VERSION 5.4 ;
NAMESCASESENSITIVE ON ;
BUSBITCHARS "[]" ;
DIVIDERCHAR "/" ;
UNITS
  DATABASE MICRONS 2000 ;
END UNITS
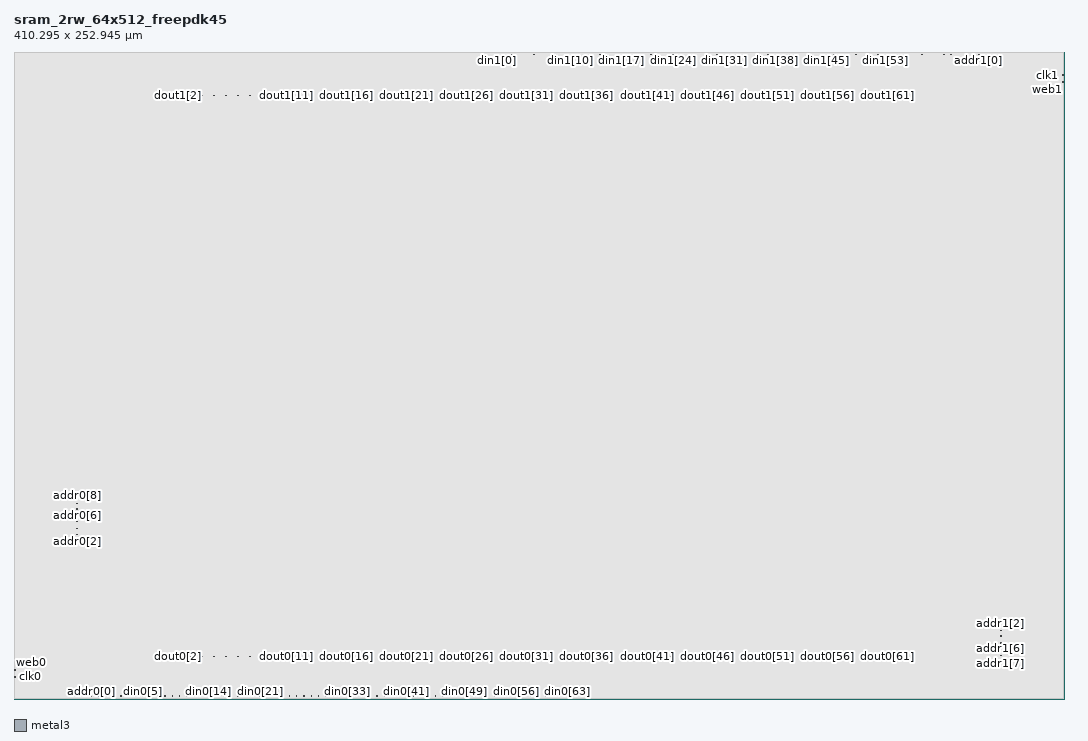
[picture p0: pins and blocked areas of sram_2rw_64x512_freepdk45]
MACRO sram_2rw_64x512_freepdk45
   CLASS BLOCK ;
   SIZE 410.295 BY 252.945 ;
   SYMMETRY X Y R90 ;
   PIN din0[0]
      DIRECTION INPUT ;
      PORT
         LAYER metal3 ;
         RECT  36.015 1.0375 36.15 1.1725 ;
      END
   END din0[0]
   PIN din0[1]
      DIRECTION INPUT ;
      PORT
         LAYER metal3 ;
         RECT  38.875 1.0375 39.01 1.1725 ;
      END
   END din0[1]
   PIN din0[2]
      DIRECTION INPUT ;
      PORT
         LAYER metal3 ;
         RECT  41.735 1.0375 41.87 1.1725 ;
      END
   END din0[2]
   PIN din0[3]
      DIRECTION INPUT ;
      PORT
         LAYER metal3 ;
         RECT  44.595 1.0375 44.73 1.1725 ;
      END
   END din0[3]
   PIN din0[4]
      DIRECTION INPUT ;
      PORT
         LAYER metal3 ;
         RECT  47.455 1.0375 47.59 1.1725 ;
      END
   END din0[4]
   PIN din0[5]
      DIRECTION INPUT ;
      PORT
         LAYER metal3 ;
         RECT  50.315 1.0375 50.45 1.1725 ;
      END
   END din0[5]
   PIN din0[6]
      DIRECTION INPUT ;
      PORT
         LAYER metal3 ;
         RECT  53.175 1.0375 53.31 1.1725 ;
      END
   END din0[6]
   PIN din0[7]
      DIRECTION INPUT ;
      PORT
         LAYER metal3 ;
         RECT  56.035 1.0375 56.17 1.1725 ;
      END
   END din0[7]
   PIN din0[8]
      DIRECTION INPUT ;
      PORT
         LAYER metal3 ;
         RECT  58.895 1.0375 59.03 1.1725 ;
      END
   END din0[8]
   PIN din0[9]
      DIRECTION INPUT ;
      PORT
         LAYER metal3 ;
         RECT  61.755 1.0375 61.89 1.1725 ;
      END
   END din0[9]
   PIN din0[10]
      DIRECTION INPUT ;
      PORT
         LAYER metal3 ;
         RECT  64.615 1.0375 64.75 1.1725 ;
      END
   END din0[10]
   PIN din0[11]
      DIRECTION INPUT ;
      PORT
         LAYER metal3 ;
         RECT  67.475 1.0375 67.61 1.1725 ;
      END
   END din0[11]
   PIN din0[12]
      DIRECTION INPUT ;
      PORT
         LAYER metal3 ;
         RECT  70.335 1.0375 70.47 1.1725 ;
      END
   END din0[12]
   PIN din0[13]
      DIRECTION INPUT ;
      PORT
         LAYER metal3 ;
         RECT  73.195 1.0375 73.33 1.1725 ;
      END
   END din0[13]
   PIN din0[14]
      DIRECTION INPUT ;
      PORT
         LAYER metal3 ;
         RECT  76.055 1.0375 76.19 1.1725 ;
      END
   END din0[14]
   PIN din0[15]
      DIRECTION INPUT ;
      PORT
         LAYER metal3 ;
         RECT  78.915 1.0375 79.05 1.1725 ;
      END
   END din0[15]
   PIN din0[16]
      DIRECTION INPUT ;
      PORT
         LAYER metal3 ;
         RECT  81.775 1.0375 81.91 1.1725 ;
      END
   END din0[16]
   PIN din0[17]
      DIRECTION INPUT ;
      PORT
         LAYER metal3 ;
         RECT  84.635 1.0375 84.77 1.1725 ;
      END
   END din0[17]
   PIN din0[18]
      DIRECTION INPUT ;
      PORT
         LAYER metal3 ;
         RECT  87.495 1.0375 87.63 1.1725 ;
      END
   END din0[18]
   PIN din0[19]
      DIRECTION INPUT ;
      PORT
         LAYER metal3 ;
         RECT  90.355 1.0375 90.49 1.1725 ;
      END
   END din0[19]
   PIN din0[20]
      DIRECTION INPUT ;
      PORT
         LAYER metal3 ;
         RECT  93.215 1.0375 93.35 1.1725 ;
      END
   END din0[20]
   PIN din0[21]
      DIRECTION INPUT ;
      PORT
         LAYER metal3 ;
         RECT  96.075 1.0375 96.21 1.1725 ;
      END
   END din0[21]
   PIN din0[22]
      DIRECTION INPUT ;
      PORT
         LAYER metal3 ;
         RECT  98.935 1.0375 99.07 1.1725 ;
      END
   END din0[22]
   PIN din0[23]
      DIRECTION INPUT ;
      PORT
         LAYER metal3 ;
         RECT  101.795 1.0375 101.93 1.1725 ;
      END
   END din0[23]
   PIN din0[24]
      DIRECTION INPUT ;
      PORT
         LAYER metal3 ;
         RECT  104.655 1.0375 104.79 1.1725 ;
      END
   END din0[24]
   PIN din0[25]
      DIRECTION INPUT ;
      PORT
         LAYER metal3 ;
         RECT  107.515 1.0375 107.65 1.1725 ;
      END
   END din0[25]
   PIN din0[26]
      DIRECTION INPUT ;
      PORT
         LAYER metal3 ;
         RECT  110.375 1.0375 110.51 1.1725 ;
      END
   END din0[26]
   PIN din0[27]
      DIRECTION INPUT ;
      PORT
         LAYER metal3 ;
         RECT  113.235 1.0375 113.37 1.1725 ;
      END
   END din0[27]
   PIN din0[28]
      DIRECTION INPUT ;
      PORT
         LAYER metal3 ;
         RECT  116.095 1.0375 116.23 1.1725 ;
      END
   END din0[28]
   PIN din0[29]
      DIRECTION INPUT ;
      PORT
         LAYER metal3 ;
         RECT  118.955 1.0375 119.09 1.1725 ;
      END
   END din0[29]
   PIN din0[30]
      DIRECTION INPUT ;
      PORT
         LAYER metal3 ;
         RECT  121.815 1.0375 121.95 1.1725 ;
      END
   END din0[30]
   PIN din0[31]
      DIRECTION INPUT ;
      PORT
         LAYER metal3 ;
         RECT  124.675 1.0375 124.81 1.1725 ;
      END
   END din0[31]
   PIN din0[32]
      DIRECTION INPUT ;
      PORT
         LAYER metal3 ;
         RECT  127.535 1.0375 127.67 1.1725 ;
      END
   END din0[32]
   PIN din0[33]
      DIRECTION INPUT ;
      PORT
         LAYER metal3 ;
         RECT  130.395 1.0375 130.53 1.1725 ;
      END
   END din0[33]
   PIN din0[34]
      DIRECTION INPUT ;
      PORT
         LAYER metal3 ;
         RECT  133.255 1.0375 133.39 1.1725 ;
      END
   END din0[34]
   PIN din0[35]
      DIRECTION INPUT ;
      PORT
         LAYER metal3 ;
         RECT  136.115 1.0375 136.25 1.1725 ;
      END
   END din0[35]
   PIN din0[36]
      DIRECTION INPUT ;
      PORT
         LAYER metal3 ;
         RECT  138.975 1.0375 139.11 1.1725 ;
      END
   END din0[36]
   PIN din0[37]
      DIRECTION INPUT ;
      PORT
         LAYER metal3 ;
         RECT  141.835 1.0375 141.97 1.1725 ;
      END
   END din0[37]
   PIN din0[38]
      DIRECTION INPUT ;
      PORT
         LAYER metal3 ;
         RECT  144.695 1.0375 144.83 1.1725 ;
      END
   END din0[38]
   PIN din0[39]
      DIRECTION INPUT ;
      PORT
         LAYER metal3 ;
         RECT  147.555 1.0375 147.69 1.1725 ;
      END
   END din0[39]
   PIN din0[40]
      DIRECTION INPUT ;
      PORT
         LAYER metal3 ;
         RECT  150.415 1.0375 150.55 1.1725 ;
      END
   END din0[40]
   PIN din0[41]
      DIRECTION INPUT ;
      PORT
         LAYER metal3 ;
         RECT  153.275 1.0375 153.41 1.1725 ;
      END
   END din0[41]
   PIN din0[42]
      DIRECTION INPUT ;
      PORT
         LAYER metal3 ;
         RECT  156.135 1.0375 156.27 1.1725 ;
      END
   END din0[42]
   PIN din0[43]
      DIRECTION INPUT ;
      PORT
         LAYER metal3 ;
         RECT  158.995 1.0375 159.13 1.1725 ;
      END
   END din0[43]
   PIN din0[44]
      DIRECTION INPUT ;
      PORT
         LAYER metal3 ;
         RECT  161.855 1.0375 161.99 1.1725 ;
      END
   END din0[44]
   PIN din0[45]
      DIRECTION INPUT ;
      PORT
         LAYER metal3 ;
         RECT  164.715 1.0375 164.85 1.1725 ;
      END
   END din0[45]
   PIN din0[46]
      DIRECTION INPUT ;
      PORT
         LAYER metal3 ;
         RECT  167.575 1.0375 167.71 1.1725 ;
      END
   END din0[46]
   PIN din0[47]
      DIRECTION INPUT ;
      PORT
         LAYER metal3 ;
         RECT  170.435 1.0375 170.57 1.1725 ;
      END
   END din0[47]
   PIN din0[48]
      DIRECTION INPUT ;
      PORT
         LAYER metal3 ;
         RECT  173.295 1.0375 173.43 1.1725 ;
      END
   END din0[48]
   PIN din0[49]
      DIRECTION INPUT ;
      PORT
         LAYER metal3 ;
         RECT  176.155 1.0375 176.29 1.1725 ;
      END
   END din0[49]
   PIN din0[50]
      DIRECTION INPUT ;
      PORT
         LAYER metal3 ;
         RECT  179.015 1.0375 179.15 1.1725 ;
      END
   END din0[50]
   PIN din0[51]
      DIRECTION INPUT ;
      PORT
         LAYER metal3 ;
         RECT  181.875 1.0375 182.01 1.1725 ;
      END
   END din0[51]
   PIN din0[52]
      DIRECTION INPUT ;
      PORT
         LAYER metal3 ;
         RECT  184.735 1.0375 184.87 1.1725 ;
      END
   END din0[52]
   PIN din0[53]
      DIRECTION INPUT ;
      PORT
         LAYER metal3 ;
         RECT  187.595 1.0375 187.73 1.1725 ;
      END
   END din0[53]
   PIN din0[54]
      DIRECTION INPUT ;
      PORT
         LAYER metal3 ;
         RECT  190.455 1.0375 190.59 1.1725 ;
      END
   END din0[54]
   PIN din0[55]
      DIRECTION INPUT ;
      PORT
         LAYER metal3 ;
         RECT  193.315 1.0375 193.45 1.1725 ;
      END
   END din0[55]
   PIN din0[56]
      DIRECTION INPUT ;
      PORT
         LAYER metal3 ;
         RECT  196.175 1.0375 196.31 1.1725 ;
      END
   END din0[56]
   PIN din0[57]
      DIRECTION INPUT ;
      PORT
         LAYER metal3 ;
         RECT  199.035 1.0375 199.17 1.1725 ;
      END
   END din0[57]
   PIN din0[58]
      DIRECTION INPUT ;
      PORT
         LAYER metal3 ;
         RECT  201.895 1.0375 202.03 1.1725 ;
      END
   END din0[58]
   PIN din0[59]
      DIRECTION INPUT ;
      PORT
         LAYER metal3 ;
         RECT  204.755 1.0375 204.89 1.1725 ;
      END
   END din0[59]
   PIN din0[60]
      DIRECTION INPUT ;
      PORT
         LAYER metal3 ;
         RECT  207.615 1.0375 207.75 1.1725 ;
      END
   END din0[60]
   PIN din0[61]
      DIRECTION INPUT ;
      PORT
         LAYER metal3 ;
         RECT  210.475 1.0375 210.61 1.1725 ;
      END
   END din0[61]
   PIN din0[62]
      DIRECTION INPUT ;
      PORT
         LAYER metal3 ;
         RECT  213.335 1.0375 213.47 1.1725 ;
      END
   END din0[62]
   PIN din0[63]
      DIRECTION INPUT ;
      PORT
         LAYER metal3 ;
         RECT  216.195 1.0375 216.33 1.1725 ;
      END
   END din0[63]
   PIN din1[0]
      DIRECTION INPUT ;
      PORT
         LAYER metal3 ;
         RECT  188.81 251.7725 188.945 251.9075 ;
      END
   END din1[0]
   PIN din1[1]
      DIRECTION INPUT ;
      PORT
         LAYER metal3 ;
         RECT  191.67 251.7725 191.805 251.9075 ;
      END
   END din1[1]
   PIN din1[2]
      DIRECTION INPUT ;
      PORT
         LAYER metal3 ;
         RECT  194.53 251.7725 194.665 251.9075 ;
      END
   END din1[2]
   PIN din1[3]
      DIRECTION INPUT ;
      PORT
         LAYER metal3 ;
         RECT  197.39 251.7725 197.525 251.9075 ;
      END
   END din1[3]
   PIN din1[4]
      DIRECTION INPUT ;
      PORT
         LAYER metal3 ;
         RECT  200.25 251.7725 200.385 251.9075 ;
      END
   END din1[4]
   PIN din1[5]
      DIRECTION INPUT ;
      PORT
         LAYER metal3 ;
         RECT  203.11 251.7725 203.245 251.9075 ;
      END
   END din1[5]
   PIN din1[6]
      DIRECTION INPUT ;
      PORT
         LAYER metal3 ;
         RECT  205.97 251.7725 206.105 251.9075 ;
      END
   END din1[6]
   PIN din1[7]
      DIRECTION INPUT ;
      PORT
         LAYER metal3 ;
         RECT  208.83 251.7725 208.965 251.9075 ;
      END
   END din1[7]
   PIN din1[8]
      DIRECTION INPUT ;
      PORT
         LAYER metal3 ;
         RECT  211.69 251.7725 211.825 251.9075 ;
      END
   END din1[8]
   PIN din1[9]
      DIRECTION INPUT ;
      PORT
         LAYER metal3 ;
         RECT  214.55 251.7725 214.685 251.9075 ;
      END
   END din1[9]
   PIN din1[10]
      DIRECTION INPUT ;
      PORT
         LAYER metal3 ;
         RECT  217.41 251.7725 217.545 251.9075 ;
      END
   END din1[10]
   PIN din1[11]
      DIRECTION INPUT ;
      PORT
         LAYER metal3 ;
         RECT  220.27 251.7725 220.405 251.9075 ;
      END
   END din1[11]
   PIN din1[12]
      DIRECTION INPUT ;
      PORT
         LAYER metal3 ;
         RECT  223.13 251.7725 223.265 251.9075 ;
      END
   END din1[12]
   PIN din1[13]
      DIRECTION INPUT ;
      PORT
         LAYER metal3 ;
         RECT  225.99 251.7725 226.125 251.9075 ;
      END
   END din1[13]
   PIN din1[14]
      DIRECTION INPUT ;
      PORT
         LAYER metal3 ;
         RECT  228.85 251.7725 228.985 251.9075 ;
      END
   END din1[14]
   PIN din1[15]
      DIRECTION INPUT ;
      PORT
         LAYER metal3 ;
         RECT  231.71 251.7725 231.845 251.9075 ;
      END
   END din1[15]
   PIN din1[16]
      DIRECTION INPUT ;
      PORT
         LAYER metal3 ;
         RECT  234.57 251.7725 234.705 251.9075 ;
      END
   END din1[16]
   PIN din1[17]
      DIRECTION INPUT ;
      PORT
         LAYER metal3 ;
         RECT  237.43 251.7725 237.565 251.9075 ;
      END
   END din1[17]
   PIN din1[18]
      DIRECTION INPUT ;
      PORT
         LAYER metal3 ;
         RECT  240.29 251.7725 240.425 251.9075 ;
      END
   END din1[18]
   PIN din1[19]
      DIRECTION INPUT ;
      PORT
         LAYER metal3 ;
         RECT  243.15 251.7725 243.285 251.9075 ;
      END
   END din1[19]
   PIN din1[20]
      DIRECTION INPUT ;
      PORT
         LAYER metal3 ;
         RECT  246.01 251.7725 246.145 251.9075 ;
      END
   END din1[20]
   PIN din1[21]
      DIRECTION INPUT ;
      PORT
         LAYER metal3 ;
         RECT  248.87 251.7725 249.005 251.9075 ;
      END
   END din1[21]
   PIN din1[22]
      DIRECTION INPUT ;
      PORT
         LAYER metal3 ;
         RECT  251.73 251.7725 251.865 251.9075 ;
      END
   END din1[22]
   PIN din1[23]
      DIRECTION INPUT ;
      PORT
         LAYER metal3 ;
         RECT  254.59 251.7725 254.725 251.9075 ;
      END
   END din1[23]
   PIN din1[24]
      DIRECTION INPUT ;
      PORT
         LAYER metal3 ;
         RECT  257.45 251.7725 257.585 251.9075 ;
      END
   END din1[24]
   PIN din1[25]
      DIRECTION INPUT ;
      PORT
         LAYER metal3 ;
         RECT  260.31 251.7725 260.445 251.9075 ;
      END
   END din1[25]
   PIN din1[26]
      DIRECTION INPUT ;
      PORT
         LAYER metal3 ;
         RECT  263.17 251.7725 263.305 251.9075 ;
      END
   END din1[26]
   PIN din1[27]
      DIRECTION INPUT ;
      PORT
         LAYER metal3 ;
         RECT  266.03 251.7725 266.165 251.9075 ;
      END
   END din1[27]
   PIN din1[28]
      DIRECTION INPUT ;
      PORT
         LAYER metal3 ;
         RECT  268.89 251.7725 269.025 251.9075 ;
      END
   END din1[28]
   PIN din1[29]
      DIRECTION INPUT ;
      PORT
         LAYER metal3 ;
         RECT  271.75 251.7725 271.885 251.9075 ;
      END
   END din1[29]
   PIN din1[30]
      DIRECTION INPUT ;
      PORT
         LAYER metal3 ;
         RECT  274.61 251.7725 274.745 251.9075 ;
      END
   END din1[30]
   PIN din1[31]
      DIRECTION INPUT ;
      PORT
         LAYER metal3 ;
         RECT  277.47 251.7725 277.605 251.9075 ;
      END
   END din1[31]
   PIN din1[32]
      DIRECTION INPUT ;
      PORT
         LAYER metal3 ;
         RECT  280.33 251.7725 280.465 251.9075 ;
      END
   END din1[32]
   PIN din1[33]
      DIRECTION INPUT ;
      PORT
         LAYER metal3 ;
         RECT  283.19 251.7725 283.325 251.9075 ;
      END
   END din1[33]
   PIN din1[34]
      DIRECTION INPUT ;
      PORT
         LAYER metal3 ;
         RECT  286.05 251.7725 286.185 251.9075 ;
      END
   END din1[34]
   PIN din1[35]
      DIRECTION INPUT ;
      PORT
         LAYER metal3 ;
         RECT  288.91 251.7725 289.045 251.9075 ;
      END
   END din1[35]
   PIN din1[36]
      DIRECTION INPUT ;
      PORT
         LAYER metal3 ;
         RECT  291.77 251.7725 291.905 251.9075 ;
      END
   END din1[36]
   PIN din1[37]
      DIRECTION INPUT ;
      PORT
         LAYER metal3 ;
         RECT  294.63 251.7725 294.765 251.9075 ;
      END
   END din1[37]
   PIN din1[38]
      DIRECTION INPUT ;
      PORT
         LAYER metal3 ;
         RECT  297.49 251.7725 297.625 251.9075 ;
      END
   END din1[38]
   PIN din1[39]
      DIRECTION INPUT ;
      PORT
         LAYER metal3 ;
         RECT  300.35 251.7725 300.485 251.9075 ;
      END
   END din1[39]
   PIN din1[40]
      DIRECTION INPUT ;
      PORT
         LAYER metal3 ;
         RECT  303.21 251.7725 303.345 251.9075 ;
      END
   END din1[40]
   PIN din1[41]
      DIRECTION INPUT ;
      PORT
         LAYER metal3 ;
         RECT  306.07 251.7725 306.205 251.9075 ;
      END
   END din1[41]
   PIN din1[42]
      DIRECTION INPUT ;
      PORT
         LAYER metal3 ;
         RECT  308.93 251.7725 309.065 251.9075 ;
      END
   END din1[42]
   PIN din1[43]
      DIRECTION INPUT ;
      PORT
         LAYER metal3 ;
         RECT  311.79 251.7725 311.925 251.9075 ;
      END
   END din1[43]
   PIN din1[44]
      DIRECTION INPUT ;
      PORT
         LAYER metal3 ;
         RECT  314.65 251.7725 314.785 251.9075 ;
      END
   END din1[44]
   PIN din1[45]
      DIRECTION INPUT ;
      PORT
         LAYER metal3 ;
         RECT  317.51 251.7725 317.645 251.9075 ;
      END
   END din1[45]
   PIN din1[46]
      DIRECTION INPUT ;
      PORT
         LAYER metal3 ;
         RECT  320.37 251.7725 320.505 251.9075 ;
      END
   END din1[46]
   PIN din1[47]
      DIRECTION INPUT ;
      PORT
         LAYER metal3 ;
         RECT  323.23 251.7725 323.365 251.9075 ;
      END
   END din1[47]
   PIN din1[48]
      DIRECTION INPUT ;
      PORT
         LAYER metal3 ;
         RECT  326.09 251.7725 326.225 251.9075 ;
      END
   END din1[48]
   PIN din1[49]
      DIRECTION INPUT ;
      PORT
         LAYER metal3 ;
         RECT  328.95 251.7725 329.085 251.9075 ;
      END
   END din1[49]
   PIN din1[50]
      DIRECTION INPUT ;
      PORT
         LAYER metal3 ;
         RECT  331.81 251.7725 331.945 251.9075 ;
      END
   END din1[50]
   PIN din1[51]
      DIRECTION INPUT ;
      PORT
         LAYER metal3 ;
         RECT  334.67 251.7725 334.805 251.9075 ;
      END
   END din1[51]
   PIN din1[52]
      DIRECTION INPUT ;
      PORT
         LAYER metal3 ;
         RECT  337.53 251.7725 337.665 251.9075 ;
      END
   END din1[52]
   PIN din1[53]
      DIRECTION INPUT ;
      PORT
         LAYER metal3 ;
         RECT  340.39 251.7725 340.525 251.9075 ;
      END
   END din1[53]
   PIN din1[54]
      DIRECTION INPUT ;
      PORT
         LAYER metal3 ;
         RECT  343.25 251.7725 343.385 251.9075 ;
      END
   END din1[54]
   PIN din1[55]
      DIRECTION INPUT ;
      PORT
         LAYER metal3 ;
         RECT  346.11 251.7725 346.245 251.9075 ;
      END
   END din1[55]
   PIN din1[56]
      DIRECTION INPUT ;
      PORT
         LAYER metal3 ;
         RECT  348.97 251.7725 349.105 251.9075 ;
      END
   END din1[56]
   PIN din1[57]
      DIRECTION INPUT ;
      PORT
         LAYER metal3 ;
         RECT  351.83 251.7725 351.965 251.9075 ;
      END
   END din1[57]
   PIN din1[58]
      DIRECTION INPUT ;
      PORT
         LAYER metal3 ;
         RECT  354.69 251.7725 354.825 251.9075 ;
      END
   END din1[58]
   PIN din1[59]
      DIRECTION INPUT ;
      PORT
         LAYER metal3 ;
         RECT  357.55 251.7725 357.685 251.9075 ;
      END
   END din1[59]
   PIN din1[60]
      DIRECTION INPUT ;
      PORT
         LAYER metal3 ;
         RECT  360.41 251.7725 360.545 251.9075 ;
      END
   END din1[60]
   PIN din1[61]
      DIRECTION INPUT ;
      PORT
         LAYER metal3 ;
         RECT  363.27 251.7725 363.405 251.9075 ;
      END
   END din1[61]
   PIN din1[62]
      DIRECTION INPUT ;
      PORT
         LAYER metal3 ;
         RECT  366.13 251.7725 366.265 251.9075 ;
      END
   END din1[62]
   PIN din1[63]
      DIRECTION INPUT ;
      PORT
         LAYER metal3 ;
         RECT  368.99 251.7725 369.125 251.9075 ;
      END
   END din1[63]
   PIN addr0[0]
      DIRECTION INPUT ;
      PORT
         LAYER metal3 ;
         RECT  30.295 1.0375 30.43 1.1725 ;
      END
   END addr0[0]
   PIN addr0[1]
      DIRECTION INPUT ;
      PORT
         LAYER metal3 ;
         RECT  33.155 1.0375 33.29 1.1725 ;
      END
   END addr0[1]
   PIN addr0[2]
      DIRECTION INPUT ;
      PORT
         LAYER metal3 ;
         RECT  24.575 61.5825 24.71 61.7175 ;
      END
   END addr0[2]
   PIN addr0[3]
      DIRECTION INPUT ;
      PORT
         LAYER metal3 ;
         RECT  24.575 64.3125 24.71 64.4475 ;
      END
   END addr0[3]
   PIN addr0[4]
      DIRECTION INPUT ;
      PORT
         LAYER metal3 ;
         RECT  24.575 66.5225 24.71 66.6575 ;
      END
   END addr0[4]
   PIN addr0[5]
      DIRECTION INPUT ;
      PORT
         LAYER metal3 ;
         RECT  24.575 69.2525 24.71 69.3875 ;
      END
   END addr0[5]
   PIN addr0[6]
      DIRECTION INPUT ;
      PORT
         LAYER metal3 ;
         RECT  24.575 71.4625 24.71 71.5975 ;
      END
   END addr0[6]
   PIN addr0[7]
      DIRECTION INPUT ;
      PORT
         LAYER metal3 ;
         RECT  24.575 74.1925 24.71 74.3275 ;
      END
   END addr0[7]
   PIN addr0[8]
      DIRECTION INPUT ;
      PORT
         LAYER metal3 ;
         RECT  24.575 76.4025 24.71 76.5375 ;
      END
   END addr0[8]
   PIN addr1[0]
      DIRECTION INPUT ;
      PORT
         LAYER metal3 ;
         RECT  377.005 251.7725 377.14 251.9075 ;
      END
   END addr1[0]
   PIN addr1[1]
      DIRECTION INPUT ;
      PORT
         LAYER metal3 ;
         RECT  374.145 251.7725 374.28 251.9075 ;
      END
   END addr1[1]
   PIN addr1[2]
      DIRECTION INPUT ;
      PORT
         LAYER metal3 ;
         RECT  385.585 29.4725 385.72 29.6075 ;
      END
   END addr1[2]
   PIN addr1[3]
      DIRECTION INPUT ;
      PORT
         LAYER metal3 ;
         RECT  385.585 26.7425 385.72 26.8775 ;
      END
   END addr1[3]
   PIN addr1[4]
      DIRECTION INPUT ;
      PORT
         LAYER metal3 ;
         RECT  385.585 24.5325 385.72 24.6675 ;
      END
   END addr1[4]
   PIN addr1[5]
      DIRECTION INPUT ;
      PORT
         LAYER metal3 ;
         RECT  385.585 21.8025 385.72 21.9375 ;
      END
   END addr1[5]
   PIN addr1[6]
      DIRECTION INPUT ;
      PORT
         LAYER metal3 ;
         RECT  385.585 19.5925 385.72 19.7275 ;
      END
   END addr1[6]
   PIN addr1[7]
      DIRECTION INPUT ;
      PORT
         LAYER metal3 ;
         RECT  385.585 16.8625 385.72 16.9975 ;
      END
   END addr1[7]
   PIN addr1[8]
      DIRECTION INPUT ;
      PORT
         LAYER metal3 ;
         RECT  385.585 14.6525 385.72 14.7875 ;
      END
   END addr1[8]
   PIN csb0
      DIRECTION INPUT ;
      PORT
         LAYER metal3 ;
         RECT  0.285 8.5425 0.42 8.6775 ;
      END
   END csb0
   PIN csb1
      DIRECTION INPUT ;
      PORT
         LAYER metal3 ;
         RECT  409.875 243.7925 410.01 243.9275 ;
      END
   END csb1
   PIN web0
      DIRECTION INPUT ;
      PORT
         LAYER metal3 ;
         RECT  0.285 11.2725 0.42 11.4075 ;
      END
   END web0
   PIN web1
      DIRECTION INPUT ;
      PORT
         LAYER metal3 ;
         RECT  409.875 241.0625 410.01 241.1975 ;
      END
   END web1
   PIN clk0
      DIRECTION INPUT ;
      PORT
         LAYER metal3 ;
         RECT  6.5275 8.6275 6.6625 8.7625 ;
      END
   END clk0
   PIN clk1
      DIRECTION INPUT ;
      PORT
         LAYER metal3 ;
         RECT  403.6325 243.7075 403.7675 243.8425 ;
      END
   END clk1
   PIN dout0[0]
      DIRECTION OUTPUT ;
      PORT
         LAYER metal3 ;
         RECT  54.61 16.47 54.745 16.605 ;
      END
   END dout0[0]
   PIN dout0[1]
      DIRECTION OUTPUT ;
      PORT
         LAYER metal3 ;
         RECT  59.31 16.47 59.445 16.605 ;
      END
   END dout0[1]
   PIN dout0[2]
      DIRECTION OUTPUT ;
      PORT
         LAYER metal3 ;
         RECT  64.01 16.47 64.145 16.605 ;
      END
   END dout0[2]
   PIN dout0[3]
      DIRECTION OUTPUT ;
      PORT
         LAYER metal3 ;
         RECT  68.71 16.47 68.845 16.605 ;
      END
   END dout0[3]
   PIN dout0[4]
      DIRECTION OUTPUT ;
      PORT
         LAYER metal3 ;
         RECT  73.41 16.47 73.545 16.605 ;
      END
   END dout0[4]
   PIN dout0[5]
      DIRECTION OUTPUT ;
      PORT
         LAYER metal3 ;
         RECT  78.11 16.47 78.245 16.605 ;
      END
   END dout0[5]
   PIN dout0[6]
      DIRECTION OUTPUT ;
      PORT
         LAYER metal3 ;
         RECT  82.81 16.47 82.945 16.605 ;
      END
   END dout0[6]
   PIN dout0[7]
      DIRECTION OUTPUT ;
      PORT
         LAYER metal3 ;
         RECT  87.51 16.47 87.645 16.605 ;
      END
   END dout0[7]
   PIN dout0[8]
      DIRECTION OUTPUT ;
      PORT
         LAYER metal3 ;
         RECT  92.21 16.47 92.345 16.605 ;
      END
   END dout0[8]
   PIN dout0[9]
      DIRECTION OUTPUT ;
      PORT
         LAYER metal3 ;
         RECT  96.91 16.47 97.045 16.605 ;
      END
   END dout0[9]
   PIN dout0[10]
      DIRECTION OUTPUT ;
      PORT
         LAYER metal3 ;
         RECT  101.61 16.47 101.745 16.605 ;
      END
   END dout0[10]
   PIN dout0[11]
      DIRECTION OUTPUT ;
      PORT
         LAYER metal3 ;
         RECT  106.31 16.47 106.445 16.605 ;
      END
   END dout0[11]
   PIN dout0[12]
      DIRECTION OUTPUT ;
      PORT
         LAYER metal3 ;
         RECT  111.01 16.47 111.145 16.605 ;
      END
   END dout0[12]
   PIN dout0[13]
      DIRECTION OUTPUT ;
      PORT
         LAYER metal3 ;
         RECT  115.71 16.47 115.845 16.605 ;
      END
   END dout0[13]
   PIN dout0[14]
      DIRECTION OUTPUT ;
      PORT
         LAYER metal3 ;
         RECT  120.41 16.47 120.545 16.605 ;
      END
   END dout0[14]
   PIN dout0[15]
      DIRECTION OUTPUT ;
      PORT
         LAYER metal3 ;
         RECT  125.11 16.47 125.245 16.605 ;
      END
   END dout0[15]
   PIN dout0[16]
      DIRECTION OUTPUT ;
      PORT
         LAYER metal3 ;
         RECT  129.81 16.47 129.945 16.605 ;
      END
   END dout0[16]
   PIN dout0[17]
      DIRECTION OUTPUT ;
      PORT
         LAYER metal3 ;
         RECT  134.51 16.47 134.645 16.605 ;
      END
   END dout0[17]
   PIN dout0[18]
      DIRECTION OUTPUT ;
      PORT
         LAYER metal3 ;
         RECT  139.21 16.47 139.345 16.605 ;
      END
   END dout0[18]
   PIN dout0[19]
      DIRECTION OUTPUT ;
      PORT
         LAYER metal3 ;
         RECT  143.91 16.47 144.045 16.605 ;
      END
   END dout0[19]
   PIN dout0[20]
      DIRECTION OUTPUT ;
      PORT
         LAYER metal3 ;
         RECT  148.61 16.47 148.745 16.605 ;
      END
   END dout0[20]
   PIN dout0[21]
      DIRECTION OUTPUT ;
      PORT
         LAYER metal3 ;
         RECT  153.31 16.47 153.445 16.605 ;
      END
   END dout0[21]
   PIN dout0[22]
      DIRECTION OUTPUT ;
      PORT
         LAYER metal3 ;
         RECT  158.01 16.47 158.145 16.605 ;
      END
   END dout0[22]
   PIN dout0[23]
      DIRECTION OUTPUT ;
      PORT
         LAYER metal3 ;
         RECT  162.71 16.47 162.845 16.605 ;
      END
   END dout0[23]
   PIN dout0[24]
      DIRECTION OUTPUT ;
      PORT
         LAYER metal3 ;
         RECT  167.41 16.47 167.545 16.605 ;
      END
   END dout0[24]
   PIN dout0[25]
      DIRECTION OUTPUT ;
      PORT
         LAYER metal3 ;
         RECT  172.11 16.47 172.245 16.605 ;
      END
   END dout0[25]
   PIN dout0[26]
      DIRECTION OUTPUT ;
      PORT
         LAYER metal3 ;
         RECT  176.81 16.47 176.945 16.605 ;
      END
   END dout0[26]
   PIN dout0[27]
      DIRECTION OUTPUT ;
      PORT
         LAYER metal3 ;
         RECT  181.51 16.47 181.645 16.605 ;
      END
   END dout0[27]
   PIN dout0[28]
      DIRECTION OUTPUT ;
      PORT
         LAYER metal3 ;
         RECT  186.21 16.47 186.345 16.605 ;
      END
   END dout0[28]
   PIN dout0[29]
      DIRECTION OUTPUT ;
      PORT
         LAYER metal3 ;
         RECT  190.91 16.47 191.045 16.605 ;
      END
   END dout0[29]
   PIN dout0[30]
      DIRECTION OUTPUT ;
      PORT
         LAYER metal3 ;
         RECT  195.61 16.47 195.745 16.605 ;
      END
   END dout0[30]
   PIN dout0[31]
      DIRECTION OUTPUT ;
      PORT
         LAYER metal3 ;
         RECT  200.31 16.47 200.445 16.605 ;
      END
   END dout0[31]
   PIN dout0[32]
      DIRECTION OUTPUT ;
      PORT
         LAYER metal3 ;
         RECT  205.01 16.47 205.145 16.605 ;
      END
   END dout0[32]
   PIN dout0[33]
      DIRECTION OUTPUT ;
      PORT
         LAYER metal3 ;
         RECT  209.71 16.47 209.845 16.605 ;
      END
   END dout0[33]
   PIN dout0[34]
      DIRECTION OUTPUT ;
      PORT
         LAYER metal3 ;
         RECT  214.41 16.47 214.545 16.605 ;
      END
   END dout0[34]
   PIN dout0[35]
      DIRECTION OUTPUT ;
      PORT
         LAYER metal3 ;
         RECT  219.11 16.47 219.245 16.605 ;
      END
   END dout0[35]
   PIN dout0[36]
      DIRECTION OUTPUT ;
      PORT
         LAYER metal3 ;
         RECT  223.81 16.47 223.945 16.605 ;
      END
   END dout0[36]
   PIN dout0[37]
      DIRECTION OUTPUT ;
      PORT
         LAYER metal3 ;
         RECT  228.51 16.47 228.645 16.605 ;
      END
   END dout0[37]
   PIN dout0[38]
      DIRECTION OUTPUT ;
      PORT
         LAYER metal3 ;
         RECT  233.21 16.47 233.345 16.605 ;
      END
   END dout0[38]
   PIN dout0[39]
      DIRECTION OUTPUT ;
      PORT
         LAYER metal3 ;
         RECT  237.91 16.47 238.045 16.605 ;
      END
   END dout0[39]
   PIN dout0[40]
      DIRECTION OUTPUT ;
      PORT
         LAYER metal3 ;
         RECT  242.61 16.47 242.745 16.605 ;
      END
   END dout0[40]
   PIN dout0[41]
      DIRECTION OUTPUT ;
      PORT
         LAYER metal3 ;
         RECT  247.31 16.47 247.445 16.605 ;
      END
   END dout0[41]
   PIN dout0[42]
      DIRECTION OUTPUT ;
      PORT
         LAYER metal3 ;
         RECT  252.01 16.47 252.145 16.605 ;
      END
   END dout0[42]
   PIN dout0[43]
      DIRECTION OUTPUT ;
      PORT
         LAYER metal3 ;
         RECT  256.71 16.47 256.845 16.605 ;
      END
   END dout0[43]
   PIN dout0[44]
      DIRECTION OUTPUT ;
      PORT
         LAYER metal3 ;
         RECT  261.41 16.47 261.545 16.605 ;
      END
   END dout0[44]
   PIN dout0[45]
      DIRECTION OUTPUT ;
      PORT
         LAYER metal3 ;
         RECT  266.11 16.47 266.245 16.605 ;
      END
   END dout0[45]
   PIN dout0[46]
      DIRECTION OUTPUT ;
      PORT
         LAYER metal3 ;
         RECT  270.81 16.47 270.945 16.605 ;
      END
   END dout0[46]
   PIN dout0[47]
      DIRECTION OUTPUT ;
      PORT
         LAYER metal3 ;
         RECT  275.51 16.47 275.645 16.605 ;
      END
   END dout0[47]
   PIN dout0[48]
      DIRECTION OUTPUT ;
      PORT
         LAYER metal3 ;
         RECT  280.21 16.47 280.345 16.605 ;
      END
   END dout0[48]
   PIN dout0[49]
      DIRECTION OUTPUT ;
      PORT
         LAYER metal3 ;
         RECT  284.91 16.47 285.045 16.605 ;
      END
   END dout0[49]
   PIN dout0[50]
      DIRECTION OUTPUT ;
      PORT
         LAYER metal3 ;
         RECT  289.61 16.47 289.745 16.605 ;
      END
   END dout0[50]
   PIN dout0[51]
      DIRECTION OUTPUT ;
      PORT
         LAYER metal3 ;
         RECT  294.31 16.47 294.445 16.605 ;
      END
   END dout0[51]
   PIN dout0[52]
      DIRECTION OUTPUT ;
      PORT
         LAYER metal3 ;
         RECT  299.01 16.47 299.145 16.605 ;
      END
   END dout0[52]
   PIN dout0[53]
      DIRECTION OUTPUT ;
      PORT
         LAYER metal3 ;
         RECT  303.71 16.47 303.845 16.605 ;
      END
   END dout0[53]
   PIN dout0[54]
      DIRECTION OUTPUT ;
      PORT
         LAYER metal3 ;
         RECT  308.41 16.47 308.545 16.605 ;
      END
   END dout0[54]
   PIN dout0[55]
      DIRECTION OUTPUT ;
      PORT
         LAYER metal3 ;
         RECT  313.11 16.47 313.245 16.605 ;
      END
   END dout0[55]
   PIN dout0[56]
      DIRECTION OUTPUT ;
      PORT
         LAYER metal3 ;
         RECT  317.81 16.47 317.945 16.605 ;
      END
   END dout0[56]
   PIN dout0[57]
      DIRECTION OUTPUT ;
      PORT
         LAYER metal3 ;
         RECT  322.51 16.47 322.645 16.605 ;
      END
   END dout0[57]
   PIN dout0[58]
      DIRECTION OUTPUT ;
      PORT
         LAYER metal3 ;
         RECT  327.21 16.47 327.345 16.605 ;
      END
   END dout0[58]
   PIN dout0[59]
      DIRECTION OUTPUT ;
      PORT
         LAYER metal3 ;
         RECT  331.91 16.47 332.045 16.605 ;
      END
   END dout0[59]
   PIN dout0[60]
      DIRECTION OUTPUT ;
      PORT
         LAYER metal3 ;
         RECT  336.61 16.47 336.745 16.605 ;
      END
   END dout0[60]
   PIN dout0[61]
      DIRECTION OUTPUT ;
      PORT
         LAYER metal3 ;
         RECT  341.31 16.47 341.445 16.605 ;
      END
   END dout0[61]
   PIN dout0[62]
      DIRECTION OUTPUT ;
      PORT
         LAYER metal3 ;
         RECT  346.01 16.47 346.145 16.605 ;
      END
   END dout0[62]
   PIN dout0[63]
      DIRECTION OUTPUT ;
      PORT
         LAYER metal3 ;
         RECT  350.71 16.47 350.845 16.605 ;
      END
   END dout0[63]
   PIN dout1[0]
      DIRECTION OUTPUT ;
      PORT
         LAYER metal3 ;
         RECT  54.61 235.865 54.745 236.0 ;
      END
   END dout1[0]
   PIN dout1[1]
      DIRECTION OUTPUT ;
      PORT
         LAYER metal3 ;
         RECT  59.31 235.865 59.445 236.0 ;
      END
   END dout1[1]
   PIN dout1[2]
      DIRECTION OUTPUT ;
      PORT
         LAYER metal3 ;
         RECT  64.01 235.865 64.145 236.0 ;
      END
   END dout1[2]
   PIN dout1[3]
      DIRECTION OUTPUT ;
      PORT
         LAYER metal3 ;
         RECT  68.71 235.865 68.845 236.0 ;
      END
   END dout1[3]
   PIN dout1[4]
      DIRECTION OUTPUT ;
      PORT
         LAYER metal3 ;
         RECT  73.41 235.865 73.545 236.0 ;
      END
   END dout1[4]
   PIN dout1[5]
      DIRECTION OUTPUT ;
      PORT
         LAYER metal3 ;
         RECT  78.11 235.865 78.245 236.0 ;
      END
   END dout1[5]
   PIN dout1[6]
      DIRECTION OUTPUT ;
      PORT
         LAYER metal3 ;
         RECT  82.81 235.865 82.945 236.0 ;
      END
   END dout1[6]
   PIN dout1[7]
      DIRECTION OUTPUT ;
      PORT
         LAYER metal3 ;
         RECT  87.51 235.865 87.645 236.0 ;
      END
   END dout1[7]
   PIN dout1[8]
      DIRECTION OUTPUT ;
      PORT
         LAYER metal3 ;
         RECT  92.21 235.865 92.345 236.0 ;
      END
   END dout1[8]
   PIN dout1[9]
      DIRECTION OUTPUT ;
      PORT
         LAYER metal3 ;
         RECT  96.91 235.865 97.045 236.0 ;
      END
   END dout1[9]
   PIN dout1[10]
      DIRECTION OUTPUT ;
      PORT
         LAYER metal3 ;
         RECT  101.61 235.865 101.745 236.0 ;
      END
   END dout1[10]
   PIN dout1[11]
      DIRECTION OUTPUT ;
      PORT
         LAYER metal3 ;
         RECT  106.31 235.865 106.445 236.0 ;
      END
   END dout1[11]
   PIN dout1[12]
      DIRECTION OUTPUT ;
      PORT
         LAYER metal3 ;
         RECT  111.01 235.865 111.145 236.0 ;
      END
   END dout1[12]
   PIN dout1[13]
      DIRECTION OUTPUT ;
      PORT
         LAYER metal3 ;
         RECT  115.71 235.865 115.845 236.0 ;
      END
   END dout1[13]
   PIN dout1[14]
      DIRECTION OUTPUT ;
      PORT
         LAYER metal3 ;
         RECT  120.41 235.865 120.545 236.0 ;
      END
   END dout1[14]
   PIN dout1[15]
      DIRECTION OUTPUT ;
      PORT
         LAYER metal3 ;
         RECT  125.11 235.865 125.245 236.0 ;
      END
   END dout1[15]
   PIN dout1[16]
      DIRECTION OUTPUT ;
      PORT
         LAYER metal3 ;
         RECT  129.81 235.865 129.945 236.0 ;
      END
   END dout1[16]
   PIN dout1[17]
      DIRECTION OUTPUT ;
      PORT
         LAYER metal3 ;
         RECT  134.51 235.865 134.645 236.0 ;
      END
   END dout1[17]
   PIN dout1[18]
      DIRECTION OUTPUT ;
      PORT
         LAYER metal3 ;
         RECT  139.21 235.865 139.345 236.0 ;
      END
   END dout1[18]
   PIN dout1[19]
      DIRECTION OUTPUT ;
      PORT
         LAYER metal3 ;
         RECT  143.91 235.865 144.045 236.0 ;
      END
   END dout1[19]
   PIN dout1[20]
      DIRECTION OUTPUT ;
      PORT
         LAYER metal3 ;
         RECT  148.61 235.865 148.745 236.0 ;
      END
   END dout1[20]
   PIN dout1[21]
      DIRECTION OUTPUT ;
      PORT
         LAYER metal3 ;
         RECT  153.31 235.865 153.445 236.0 ;
      END
   END dout1[21]
   PIN dout1[22]
      DIRECTION OUTPUT ;
      PORT
         LAYER metal3 ;
         RECT  158.01 235.865 158.145 236.0 ;
      END
   END dout1[22]
   PIN dout1[23]
      DIRECTION OUTPUT ;
      PORT
         LAYER metal3 ;
         RECT  162.71 235.865 162.845 236.0 ;
      END
   END dout1[23]
   PIN dout1[24]
      DIRECTION OUTPUT ;
      PORT
         LAYER metal3 ;
         RECT  167.41 235.865 167.545 236.0 ;
      END
   END dout1[24]
   PIN dout1[25]
      DIRECTION OUTPUT ;
      PORT
         LAYER metal3 ;
         RECT  172.11 235.865 172.245 236.0 ;
      END
   END dout1[25]
   PIN dout1[26]
      DIRECTION OUTPUT ;
      PORT
         LAYER metal3 ;
         RECT  176.81 235.865 176.945 236.0 ;
      END
   END dout1[26]
   PIN dout1[27]
      DIRECTION OUTPUT ;
      PORT
         LAYER metal3 ;
         RECT  181.51 235.865 181.645 236.0 ;
      END
   END dout1[27]
   PIN dout1[28]
      DIRECTION OUTPUT ;
      PORT
         LAYER metal3 ;
         RECT  186.21 235.865 186.345 236.0 ;
      END
   END dout1[28]
   PIN dout1[29]
      DIRECTION OUTPUT ;
      PORT
         LAYER metal3 ;
         RECT  190.91 235.865 191.045 236.0 ;
      END
   END dout1[29]
   PIN dout1[30]
      DIRECTION OUTPUT ;
      PORT
         LAYER metal3 ;
         RECT  195.61 235.865 195.745 236.0 ;
      END
   END dout1[30]
   PIN dout1[31]
      DIRECTION OUTPUT ;
      PORT
         LAYER metal3 ;
         RECT  200.31 235.865 200.445 236.0 ;
      END
   END dout1[31]
   PIN dout1[32]
      DIRECTION OUTPUT ;
      PORT
         LAYER metal3 ;
         RECT  205.01 235.865 205.145 236.0 ;
      END
   END dout1[32]
   PIN dout1[33]
      DIRECTION OUTPUT ;
      PORT
         LAYER metal3 ;
         RECT  209.71 235.865 209.845 236.0 ;
      END
   END dout1[33]
   PIN dout1[34]
      DIRECTION OUTPUT ;
      PORT
         LAYER metal3 ;
         RECT  214.41 235.865 214.545 236.0 ;
      END
   END dout1[34]
   PIN dout1[35]
      DIRECTION OUTPUT ;
      PORT
         LAYER metal3 ;
         RECT  219.11 235.865 219.245 236.0 ;
      END
   END dout1[35]
   PIN dout1[36]
      DIRECTION OUTPUT ;
      PORT
         LAYER metal3 ;
         RECT  223.81 235.865 223.945 236.0 ;
      END
   END dout1[36]
   PIN dout1[37]
      DIRECTION OUTPUT ;
      PORT
         LAYER metal3 ;
         RECT  228.51 235.865 228.645 236.0 ;
      END
   END dout1[37]
   PIN dout1[38]
      DIRECTION OUTPUT ;
      PORT
         LAYER metal3 ;
         RECT  233.21 235.865 233.345 236.0 ;
      END
   END dout1[38]
   PIN dout1[39]
      DIRECTION OUTPUT ;
      PORT
         LAYER metal3 ;
         RECT  237.91 235.865 238.045 236.0 ;
      END
   END dout1[39]
   PIN dout1[40]
      DIRECTION OUTPUT ;
      PORT
         LAYER metal3 ;
         RECT  242.61 235.865 242.745 236.0 ;
      END
   END dout1[40]
   PIN dout1[41]
      DIRECTION OUTPUT ;
      PORT
         LAYER metal3 ;
         RECT  247.31 235.865 247.445 236.0 ;
      END
   END dout1[41]
   PIN dout1[42]
      DIRECTION OUTPUT ;
      PORT
         LAYER metal3 ;
         RECT  252.01 235.865 252.145 236.0 ;
      END
   END dout1[42]
   PIN dout1[43]
      DIRECTION OUTPUT ;
      PORT
         LAYER metal3 ;
         RECT  256.71 235.865 256.845 236.0 ;
      END
   END dout1[43]
   PIN dout1[44]
      DIRECTION OUTPUT ;
      PORT
         LAYER metal3 ;
         RECT  261.41 235.865 261.545 236.0 ;
      END
   END dout1[44]
   PIN dout1[45]
      DIRECTION OUTPUT ;
      PORT
         LAYER metal3 ;
         RECT  266.11 235.865 266.245 236.0 ;
      END
   END dout1[45]
   PIN dout1[46]
      DIRECTION OUTPUT ;
      PORT
         LAYER metal3 ;
         RECT  270.81 235.865 270.945 236.0 ;
      END
   END dout1[46]
   PIN dout1[47]
      DIRECTION OUTPUT ;
      PORT
         LAYER metal3 ;
         RECT  275.51 235.865 275.645 236.0 ;
      END
   END dout1[47]
   PIN dout1[48]
      DIRECTION OUTPUT ;
      PORT
         LAYER metal3 ;
         RECT  280.21 235.865 280.345 236.0 ;
      END
   END dout1[48]
   PIN dout1[49]
      DIRECTION OUTPUT ;
      PORT
         LAYER metal3 ;
         RECT  284.91 235.865 285.045 236.0 ;
      END
   END dout1[49]
   PIN dout1[50]
      DIRECTION OUTPUT ;
      PORT
         LAYER metal3 ;
         RECT  289.61 235.865 289.745 236.0 ;
      END
   END dout1[50]
   PIN dout1[51]
      DIRECTION OUTPUT ;
      PORT
         LAYER metal3 ;
         RECT  294.31 235.865 294.445 236.0 ;
      END
   END dout1[51]
   PIN dout1[52]
      DIRECTION OUTPUT ;
      PORT
         LAYER metal3 ;
         RECT  299.01 235.865 299.145 236.0 ;
      END
   END dout1[52]
   PIN dout1[53]
      DIRECTION OUTPUT ;
      PORT
         LAYER metal3 ;
         RECT  303.71 235.865 303.845 236.0 ;
      END
   END dout1[53]
   PIN dout1[54]
      DIRECTION OUTPUT ;
      PORT
         LAYER metal3 ;
         RECT  308.41 235.865 308.545 236.0 ;
      END
   END dout1[54]
   PIN dout1[55]
      DIRECTION OUTPUT ;
      PORT
         LAYER metal3 ;
         RECT  313.11 235.865 313.245 236.0 ;
      END
   END dout1[55]
   PIN dout1[56]
      DIRECTION OUTPUT ;
      PORT
         LAYER metal3 ;
         RECT  317.81 235.865 317.945 236.0 ;
      END
   END dout1[56]
   PIN dout1[57]
      DIRECTION OUTPUT ;
      PORT
         LAYER metal3 ;
         RECT  322.51 235.865 322.645 236.0 ;
      END
   END dout1[57]
   PIN dout1[58]
      DIRECTION OUTPUT ;
      PORT
         LAYER metal3 ;
         RECT  327.21 235.865 327.345 236.0 ;
      END
   END dout1[58]
   PIN dout1[59]
      DIRECTION OUTPUT ;
      PORT
         LAYER metal3 ;
         RECT  331.91 235.865 332.045 236.0 ;
      END
   END dout1[59]
   PIN dout1[60]
      DIRECTION OUTPUT ;
      PORT
         LAYER metal3 ;
         RECT  336.61 235.865 336.745 236.0 ;
      END
   END dout1[60]
   PIN dout1[61]
      DIRECTION OUTPUT ;
      PORT
         LAYER metal3 ;
         RECT  341.31 235.865 341.445 236.0 ;
      END
   END dout1[61]
   PIN dout1[62]
      DIRECTION OUTPUT ;
      PORT
         LAYER metal3 ;
         RECT  346.01 235.865 346.145 236.0 ;
      END
   END dout1[62]
   PIN dout1[63]
      DIRECTION OUTPUT ;
      PORT
         LAYER metal3 ;
         RECT  350.71 235.865 350.845 236.0 ;
      END
   END dout1[63]
   PIN vdd
      DIRECTION INOUT ;
      USE POWER ; 
      SHAPE ABUTMENT ; 
      PORT
      END
   END vdd
   PIN gnd
      DIRECTION INOUT ;
      USE GROUND ; 
      SHAPE ABUTMENT ; 
      PORT
      END
   END gnd
   OBS
   LAYER  metal1 ;
      RECT  0.14 0.14 410.155 252.805 ;
   LAYER  metal2 ;
      RECT  0.14 0.14 410.155 252.805 ;
   LAYER  metal3 ;
      RECT  0.14 0.14 35.875 0.8975 ;
      RECT  35.875 0.14 36.29 0.8975 ;
      RECT  35.875 1.3125 36.29 252.805 ;
      RECT  36.29 0.14 410.155 0.8975 ;
      RECT  36.29 0.8975 38.735 1.3125 ;
      RECT  39.15 0.8975 41.595 1.3125 ;
      RECT  42.01 0.8975 44.455 1.3125 ;
      RECT  44.87 0.8975 47.315 1.3125 ;
      RECT  47.73 0.8975 50.175 1.3125 ;
      RECT  50.59 0.8975 53.035 1.3125 ;
      RECT  53.45 0.8975 55.895 1.3125 ;
      RECT  56.31 0.8975 58.755 1.3125 ;
      RECT  59.17 0.8975 61.615 1.3125 ;
      RECT  62.03 0.8975 64.475 1.3125 ;
      RECT  64.89 0.8975 67.335 1.3125 ;
      RECT  67.75 0.8975 70.195 1.3125 ;
      RECT  70.61 0.8975 73.055 1.3125 ;
      RECT  73.47 0.8975 75.915 1.3125 ;
      RECT  76.33 0.8975 78.775 1.3125 ;
      RECT  79.19 0.8975 81.635 1.3125 ;
      RECT  82.05 0.8975 84.495 1.3125 ;
      RECT  84.91 0.8975 87.355 1.3125 ;
      RECT  87.77 0.8975 90.215 1.3125 ;
      RECT  90.63 0.8975 93.075 1.3125 ;
      RECT  93.49 0.8975 95.935 1.3125 ;
      RECT  96.35 0.8975 98.795 1.3125 ;
      RECT  99.21 0.8975 101.655 1.3125 ;
      RECT  102.07 0.8975 104.515 1.3125 ;
      RECT  104.93 0.8975 107.375 1.3125 ;
      RECT  107.79 0.8975 110.235 1.3125 ;
      RECT  110.65 0.8975 113.095 1.3125 ;
      RECT  113.51 0.8975 115.955 1.3125 ;
      RECT  116.37 0.8975 118.815 1.3125 ;
      RECT  119.23 0.8975 121.675 1.3125 ;
      RECT  122.09 0.8975 124.535 1.3125 ;
      RECT  124.95 0.8975 127.395 1.3125 ;
      RECT  127.81 0.8975 130.255 1.3125 ;
      RECT  130.67 0.8975 133.115 1.3125 ;
      RECT  133.53 0.8975 135.975 1.3125 ;
      RECT  136.39 0.8975 138.835 1.3125 ;
      RECT  139.25 0.8975 141.695 1.3125 ;
      RECT  142.11 0.8975 144.555 1.3125 ;
      RECT  144.97 0.8975 147.415 1.3125 ;
      RECT  147.83 0.8975 150.275 1.3125 ;
      RECT  150.69 0.8975 153.135 1.3125 ;
      RECT  153.55 0.8975 155.995 1.3125 ;
      RECT  156.41 0.8975 158.855 1.3125 ;
      RECT  159.27 0.8975 161.715 1.3125 ;
      RECT  162.13 0.8975 164.575 1.3125 ;
      RECT  164.99 0.8975 167.435 1.3125 ;
      RECT  167.85 0.8975 170.295 1.3125 ;
      RECT  170.71 0.8975 173.155 1.3125 ;
      RECT  173.57 0.8975 176.015 1.3125 ;
      RECT  176.43 0.8975 178.875 1.3125 ;
      RECT  179.29 0.8975 181.735 1.3125 ;
      RECT  182.15 0.8975 184.595 1.3125 ;
      RECT  185.01 0.8975 187.455 1.3125 ;
      RECT  187.87 0.8975 190.315 1.3125 ;
      RECT  190.73 0.8975 193.175 1.3125 ;
      RECT  193.59 0.8975 196.035 1.3125 ;
      RECT  196.45 0.8975 198.895 1.3125 ;
      RECT  199.31 0.8975 201.755 1.3125 ;
      RECT  202.17 0.8975 204.615 1.3125 ;
      RECT  205.03 0.8975 207.475 1.3125 ;
      RECT  207.89 0.8975 210.335 1.3125 ;
      RECT  210.75 0.8975 213.195 1.3125 ;
      RECT  213.61 0.8975 216.055 1.3125 ;
      RECT  216.47 0.8975 410.155 1.3125 ;
      RECT  36.29 251.6325 188.67 252.0475 ;
      RECT  36.29 252.0475 188.67 252.805 ;
      RECT  188.67 1.3125 189.085 251.6325 ;
      RECT  188.67 252.0475 189.085 252.805 ;
      RECT  189.085 252.0475 410.155 252.805 ;
      RECT  189.085 251.6325 191.53 252.0475 ;
      RECT  191.945 251.6325 194.39 252.0475 ;
      RECT  194.805 251.6325 197.25 252.0475 ;
      RECT  197.665 251.6325 200.11 252.0475 ;
      RECT  200.525 251.6325 202.97 252.0475 ;
      RECT  203.385 251.6325 205.83 252.0475 ;
      RECT  206.245 251.6325 208.69 252.0475 ;
      RECT  209.105 251.6325 211.55 252.0475 ;
      RECT  211.965 251.6325 214.41 252.0475 ;
      RECT  214.825 251.6325 217.27 252.0475 ;
      RECT  217.685 251.6325 220.13 252.0475 ;
      RECT  220.545 251.6325 222.99 252.0475 ;
      RECT  223.405 251.6325 225.85 252.0475 ;
      RECT  226.265 251.6325 228.71 252.0475 ;
      RECT  229.125 251.6325 231.57 252.0475 ;
      RECT  231.985 251.6325 234.43 252.0475 ;
      RECT  234.845 251.6325 237.29 252.0475 ;
      RECT  237.705 251.6325 240.15 252.0475 ;
      RECT  240.565 251.6325 243.01 252.0475 ;
      RECT  243.425 251.6325 245.87 252.0475 ;
      RECT  246.285 251.6325 248.73 252.0475 ;
      RECT  249.145 251.6325 251.59 252.0475 ;
      RECT  252.005 251.6325 254.45 252.0475 ;
      RECT  254.865 251.6325 257.31 252.0475 ;
      RECT  257.725 251.6325 260.17 252.0475 ;
      RECT  260.585 251.6325 263.03 252.0475 ;
      RECT  263.445 251.6325 265.89 252.0475 ;
      RECT  266.305 251.6325 268.75 252.0475 ;
      RECT  269.165 251.6325 271.61 252.0475 ;
      RECT  272.025 251.6325 274.47 252.0475 ;
      RECT  274.885 251.6325 277.33 252.0475 ;
      RECT  277.745 251.6325 280.19 252.0475 ;
      RECT  280.605 251.6325 283.05 252.0475 ;
      RECT  283.465 251.6325 285.91 252.0475 ;
      RECT  286.325 251.6325 288.77 252.0475 ;
      RECT  289.185 251.6325 291.63 252.0475 ;
      RECT  292.045 251.6325 294.49 252.0475 ;
      RECT  294.905 251.6325 297.35 252.0475 ;
      RECT  297.765 251.6325 300.21 252.0475 ;
      RECT  300.625 251.6325 303.07 252.0475 ;
      RECT  303.485 251.6325 305.93 252.0475 ;
      RECT  306.345 251.6325 308.79 252.0475 ;
      RECT  309.205 251.6325 311.65 252.0475 ;
      RECT  312.065 251.6325 314.51 252.0475 ;
      RECT  314.925 251.6325 317.37 252.0475 ;
      RECT  317.785 251.6325 320.23 252.0475 ;
      RECT  320.645 251.6325 323.09 252.0475 ;
      RECT  323.505 251.6325 325.95 252.0475 ;
      RECT  326.365 251.6325 328.81 252.0475 ;
      RECT  329.225 251.6325 331.67 252.0475 ;
      RECT  332.085 251.6325 334.53 252.0475 ;
      RECT  334.945 251.6325 337.39 252.0475 ;
      RECT  337.805 251.6325 340.25 252.0475 ;
      RECT  340.665 251.6325 343.11 252.0475 ;
      RECT  343.525 251.6325 345.97 252.0475 ;
      RECT  346.385 251.6325 348.83 252.0475 ;
      RECT  349.245 251.6325 351.69 252.0475 ;
      RECT  352.105 251.6325 354.55 252.0475 ;
      RECT  354.965 251.6325 357.41 252.0475 ;
      RECT  357.825 251.6325 360.27 252.0475 ;
      RECT  360.685 251.6325 363.13 252.0475 ;
      RECT  363.545 251.6325 365.99 252.0475 ;
      RECT  366.405 251.6325 368.85 252.0475 ;
      RECT  0.14 0.8975 30.155 1.3125 ;
      RECT  30.57 0.8975 33.015 1.3125 ;
      RECT  33.43 0.8975 35.875 1.3125 ;
      RECT  0.14 61.4425 24.435 61.8575 ;
      RECT  0.14 61.8575 24.435 252.805 ;
      RECT  24.435 1.3125 24.85 61.4425 ;
      RECT  24.85 1.3125 35.875 61.4425 ;
      RECT  24.85 61.4425 35.875 61.8575 ;
      RECT  24.85 61.8575 35.875 252.805 ;
      RECT  24.435 61.8575 24.85 64.1725 ;
      RECT  24.435 64.5875 24.85 66.3825 ;
      RECT  24.435 66.7975 24.85 69.1125 ;
      RECT  24.435 69.5275 24.85 71.3225 ;
      RECT  24.435 71.7375 24.85 74.0525 ;
      RECT  24.435 74.4675 24.85 76.2625 ;
      RECT  24.435 76.6775 24.85 252.805 ;
      RECT  377.28 251.6325 410.155 252.0475 ;
      RECT  369.265 251.6325 374.005 252.0475 ;
      RECT  374.42 251.6325 376.865 252.0475 ;
      RECT  189.085 29.3325 385.445 29.7475 ;
      RECT  385.445 29.7475 385.86 251.6325 ;
      RECT  385.86 1.3125 410.155 29.3325 ;
      RECT  385.86 29.3325 410.155 29.7475 ;
      RECT  385.445 27.0175 385.86 29.3325 ;
      RECT  385.445 24.8075 385.86 26.6025 ;
      RECT  385.445 22.0775 385.86 24.3925 ;
      RECT  385.445 19.8675 385.86 21.6625 ;
      RECT  385.445 17.1375 385.86 19.4525 ;
      RECT  385.445 1.3125 385.86 14.5125 ;
      RECT  385.445 14.9275 385.86 16.7225 ;
      RECT  0.14 1.3125 0.145 8.4025 ;
      RECT  0.14 8.4025 0.145 8.8175 ;
      RECT  0.14 8.8175 0.145 61.4425 ;
      RECT  0.145 1.3125 0.56 8.4025 ;
      RECT  0.56 1.3125 24.435 8.4025 ;
      RECT  385.86 244.0675 409.735 251.6325 ;
      RECT  409.735 244.0675 410.15 251.6325 ;
      RECT  410.15 29.7475 410.155 243.6525 ;
      RECT  410.15 243.6525 410.155 244.0675 ;
      RECT  410.15 244.0675 410.155 251.6325 ;
      RECT  0.145 8.8175 0.56 11.1325 ;
      RECT  0.145 11.5475 0.56 61.4425 ;
      RECT  409.735 29.7475 410.15 240.9225 ;
      RECT  409.735 241.3375 410.15 243.6525 ;
      RECT  0.56 8.4025 6.3875 8.4875 ;
      RECT  0.56 8.4875 6.3875 8.8175 ;
      RECT  6.3875 8.4025 6.8025 8.4875 ;
      RECT  6.8025 8.4025 24.435 8.4875 ;
      RECT  6.8025 8.4875 24.435 8.8175 ;
      RECT  0.56 8.8175 6.3875 8.9025 ;
      RECT  0.56 8.9025 6.3875 61.4425 ;
      RECT  6.3875 8.9025 6.8025 61.4425 ;
      RECT  6.8025 8.8175 24.435 8.9025 ;
      RECT  6.8025 8.9025 24.435 61.4425 ;
      RECT  385.86 29.7475 403.4925 243.5675 ;
      RECT  385.86 243.5675 403.4925 243.6525 ;
      RECT  403.4925 29.7475 403.9075 243.5675 ;
      RECT  403.9075 29.7475 409.735 243.5675 ;
      RECT  403.9075 243.5675 409.735 243.6525 ;
      RECT  385.86 243.6525 403.4925 243.9825 ;
      RECT  385.86 243.9825 403.4925 244.0675 ;
      RECT  403.4925 243.9825 403.9075 244.0675 ;
      RECT  403.9075 243.6525 409.735 243.9825 ;
      RECT  403.9075 243.9825 409.735 244.0675 ;
      RECT  36.29 1.3125 54.47 16.33 ;
      RECT  36.29 16.33 54.47 16.745 ;
      RECT  36.29 16.745 54.47 251.6325 ;
      RECT  54.47 1.3125 54.885 16.33 ;
      RECT  54.885 1.3125 188.67 16.33 ;
      RECT  54.885 16.33 59.17 16.745 ;
      RECT  59.585 16.33 63.87 16.745 ;
      RECT  64.285 16.33 68.57 16.745 ;
      RECT  68.985 16.33 73.27 16.745 ;
      RECT  73.685 16.33 77.97 16.745 ;
      RECT  78.385 16.33 82.67 16.745 ;
      RECT  83.085 16.33 87.37 16.745 ;
      RECT  87.785 16.33 92.07 16.745 ;
      RECT  92.485 16.33 96.77 16.745 ;
      RECT  97.185 16.33 101.47 16.745 ;
      RECT  101.885 16.33 106.17 16.745 ;
      RECT  106.585 16.33 110.87 16.745 ;
      RECT  111.285 16.33 115.57 16.745 ;
      RECT  115.985 16.33 120.27 16.745 ;
      RECT  120.685 16.33 124.97 16.745 ;
      RECT  125.385 16.33 129.67 16.745 ;
      RECT  130.085 16.33 134.37 16.745 ;
      RECT  134.785 16.33 139.07 16.745 ;
      RECT  139.485 16.33 143.77 16.745 ;
      RECT  144.185 16.33 148.47 16.745 ;
      RECT  148.885 16.33 153.17 16.745 ;
      RECT  153.585 16.33 157.87 16.745 ;
      RECT  158.285 16.33 162.57 16.745 ;
      RECT  162.985 16.33 167.27 16.745 ;
      RECT  167.685 16.33 171.97 16.745 ;
      RECT  172.385 16.33 176.67 16.745 ;
      RECT  177.085 16.33 181.37 16.745 ;
      RECT  181.785 16.33 186.07 16.745 ;
      RECT  186.485 16.33 188.67 16.745 ;
      RECT  189.085 1.3125 190.77 16.33 ;
      RECT  189.085 16.33 190.77 16.745 ;
      RECT  189.085 16.745 190.77 29.3325 ;
      RECT  190.77 1.3125 191.185 16.33 ;
      RECT  190.77 16.745 191.185 29.3325 ;
      RECT  191.185 1.3125 385.445 16.33 ;
      RECT  191.185 16.745 385.445 29.3325 ;
      RECT  191.185 16.33 195.47 16.745 ;
      RECT  195.885 16.33 200.17 16.745 ;
      RECT  200.585 16.33 204.87 16.745 ;
      RECT  205.285 16.33 209.57 16.745 ;
      RECT  209.985 16.33 214.27 16.745 ;
      RECT  214.685 16.33 218.97 16.745 ;
      RECT  219.385 16.33 223.67 16.745 ;
      RECT  224.085 16.33 228.37 16.745 ;
      RECT  228.785 16.33 233.07 16.745 ;
      RECT  233.485 16.33 237.77 16.745 ;
      RECT  238.185 16.33 242.47 16.745 ;
      RECT  242.885 16.33 247.17 16.745 ;
      RECT  247.585 16.33 251.87 16.745 ;
      RECT  252.285 16.33 256.57 16.745 ;
      RECT  256.985 16.33 261.27 16.745 ;
      RECT  261.685 16.33 265.97 16.745 ;
      RECT  266.385 16.33 270.67 16.745 ;
      RECT  271.085 16.33 275.37 16.745 ;
      RECT  275.785 16.33 280.07 16.745 ;
      RECT  280.485 16.33 284.77 16.745 ;
      RECT  285.185 16.33 289.47 16.745 ;
      RECT  289.885 16.33 294.17 16.745 ;
      RECT  294.585 16.33 298.87 16.745 ;
      RECT  299.285 16.33 303.57 16.745 ;
      RECT  303.985 16.33 308.27 16.745 ;
      RECT  308.685 16.33 312.97 16.745 ;
      RECT  313.385 16.33 317.67 16.745 ;
      RECT  318.085 16.33 322.37 16.745 ;
      RECT  322.785 16.33 327.07 16.745 ;
      RECT  327.485 16.33 331.77 16.745 ;
      RECT  332.185 16.33 336.47 16.745 ;
      RECT  336.885 16.33 341.17 16.745 ;
      RECT  341.585 16.33 345.87 16.745 ;
      RECT  346.285 16.33 350.57 16.745 ;
      RECT  350.985 16.33 385.445 16.745 ;
      RECT  54.47 16.745 54.885 235.725 ;
      RECT  54.47 236.14 54.885 251.6325 ;
      RECT  54.885 16.745 59.17 235.725 ;
      RECT  54.885 235.725 59.17 236.14 ;
      RECT  54.885 236.14 59.17 251.6325 ;
      RECT  59.17 16.745 59.585 235.725 ;
      RECT  59.17 236.14 59.585 251.6325 ;
      RECT  59.585 16.745 188.67 235.725 ;
      RECT  59.585 236.14 188.67 251.6325 ;
      RECT  59.585 235.725 63.87 236.14 ;
      RECT  64.285 235.725 68.57 236.14 ;
      RECT  68.985 235.725 73.27 236.14 ;
      RECT  73.685 235.725 77.97 236.14 ;
      RECT  78.385 235.725 82.67 236.14 ;
      RECT  83.085 235.725 87.37 236.14 ;
      RECT  87.785 235.725 92.07 236.14 ;
      RECT  92.485 235.725 96.77 236.14 ;
      RECT  97.185 235.725 101.47 236.14 ;
      RECT  101.885 235.725 106.17 236.14 ;
      RECT  106.585 235.725 110.87 236.14 ;
      RECT  111.285 235.725 115.57 236.14 ;
      RECT  115.985 235.725 120.27 236.14 ;
      RECT  120.685 235.725 124.97 236.14 ;
      RECT  125.385 235.725 129.67 236.14 ;
      RECT  130.085 235.725 134.37 236.14 ;
      RECT  134.785 235.725 139.07 236.14 ;
      RECT  139.485 235.725 143.77 236.14 ;
      RECT  144.185 235.725 148.47 236.14 ;
      RECT  148.885 235.725 153.17 236.14 ;
      RECT  153.585 235.725 157.87 236.14 ;
      RECT  158.285 235.725 162.57 236.14 ;
      RECT  162.985 235.725 167.27 236.14 ;
      RECT  167.685 235.725 171.97 236.14 ;
      RECT  172.385 235.725 176.67 236.14 ;
      RECT  177.085 235.725 181.37 236.14 ;
      RECT  181.785 235.725 186.07 236.14 ;
      RECT  186.485 235.725 188.67 236.14 ;
      RECT  189.085 29.7475 190.77 235.725 ;
      RECT  189.085 235.725 190.77 236.14 ;
      RECT  189.085 236.14 190.77 251.6325 ;
      RECT  190.77 29.7475 191.185 235.725 ;
      RECT  190.77 236.14 191.185 251.6325 ;
      RECT  191.185 29.7475 385.445 235.725 ;
      RECT  191.185 236.14 385.445 251.6325 ;
      RECT  191.185 235.725 195.47 236.14 ;
      RECT  195.885 235.725 200.17 236.14 ;
      RECT  200.585 235.725 204.87 236.14 ;
      RECT  205.285 235.725 209.57 236.14 ;
      RECT  209.985 235.725 214.27 236.14 ;
      RECT  214.685 235.725 218.97 236.14 ;
      RECT  219.385 235.725 223.67 236.14 ;
      RECT  224.085 235.725 228.37 236.14 ;
      RECT  228.785 235.725 233.07 236.14 ;
      RECT  233.485 235.725 237.77 236.14 ;
      RECT  238.185 235.725 242.47 236.14 ;
      RECT  242.885 235.725 247.17 236.14 ;
      RECT  247.585 235.725 251.87 236.14 ;
      RECT  252.285 235.725 256.57 236.14 ;
      RECT  256.985 235.725 261.27 236.14 ;
      RECT  261.685 235.725 265.97 236.14 ;
      RECT  266.385 235.725 270.67 236.14 ;
      RECT  271.085 235.725 275.37 236.14 ;
      RECT  275.785 235.725 280.07 236.14 ;
      RECT  280.485 235.725 284.77 236.14 ;
      RECT  285.185 235.725 289.47 236.14 ;
      RECT  289.885 235.725 294.17 236.14 ;
      RECT  294.585 235.725 298.87 236.14 ;
      RECT  299.285 235.725 303.57 236.14 ;
      RECT  303.985 235.725 308.27 236.14 ;
      RECT  308.685 235.725 312.97 236.14 ;
      RECT  313.385 235.725 317.67 236.14 ;
      RECT  318.085 235.725 322.37 236.14 ;
      RECT  322.785 235.725 327.07 236.14 ;
      RECT  327.485 235.725 331.77 236.14 ;
      RECT  332.185 235.725 336.47 236.14 ;
      RECT  336.885 235.725 341.17 236.14 ;
      RECT  341.585 235.725 345.87 236.14 ;
      RECT  346.285 235.725 350.57 236.14 ;
      RECT  350.985 235.725 385.445 236.14 ;
   LAYER  metal4 ;
      RECT  0.14 0.14 410.155 252.805 ;
   END
END    sram_2rw_64x512_freepdk45
END    LIBRARY
